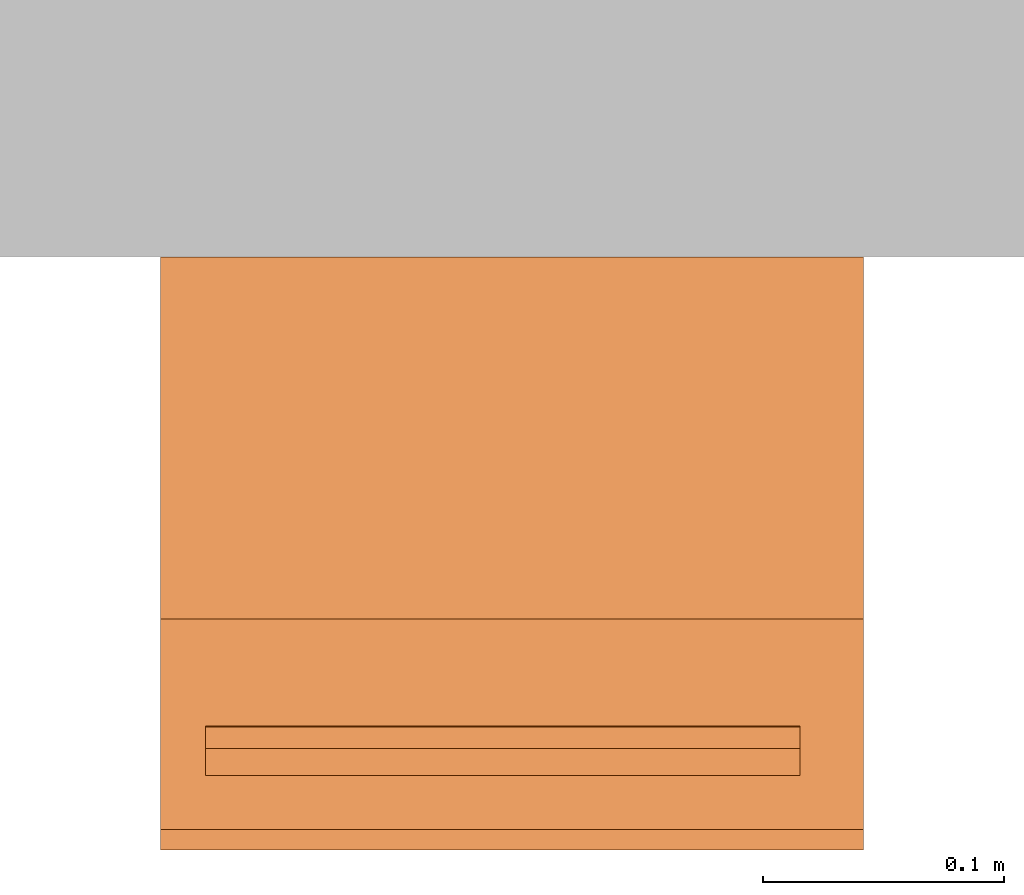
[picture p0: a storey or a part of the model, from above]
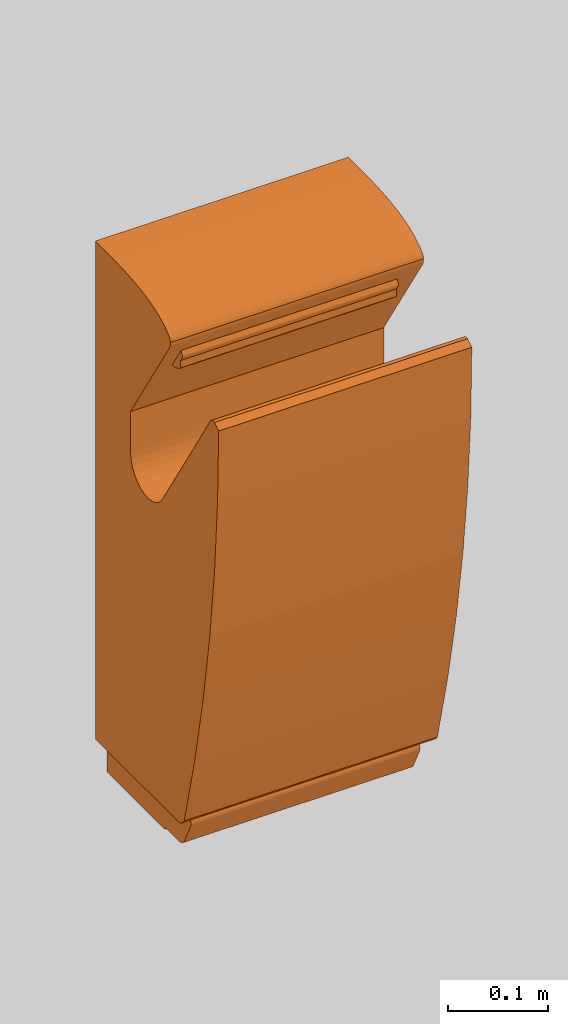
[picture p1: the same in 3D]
Properties of the parts of a building model (IFC2X3)

# File
Description: ViewDefinition [CoordinationView]
File name: Project Number
Time: 2016-07-05T09:52:08
Written by: Autodesk Revit Architecture 2011 - 1.0
Made in: 20100326_1700(x64)

# IfcProject, Project Number
Phase: Project Status

# IfcSite, Default
RefLatitude: 42, 21, 30, 344238; RefLongitude: -71, -3, -35, -194702; RefElevation: 0 mm

# IfcBuilding
Pset_BuildingCommon - NumberOfStoreys: 1
PSet_Revit_Other - Project Issue Date: Issue Date; Project Status: Project Status; Client Name: Owner; Project Address: Enter address here; Project Name: Project Name; Project Number: Project Number

# IfcBuildingStorey, Level 1
Elevation: 0 mm
PSet_Revit_Identity Data - Name: Level 1
PSet_Revit_Constraints - Elevation: 0 mm
PSet_Revit_Type_Graphics - Line Weight: 1; Color: 0; Line Pattern: Centre; Symbol: M_Level Head - Circle; Symbol at End 1 Default: no; Symbol at End 2 Default: yes
PSet_Revit_Type_Constraints - Elevation Base: 0
PSet_Revit_Type_Dimensions - Automatic Room Computation Height: no; Computation Height: 1200 mm

# IfcBuildingElementProxy: Type 1, 510621-2-FR:Type 1:Type 1:229480
In: Level 1
PSet_Revit_Constraints - Level: Level 1; Elevation: 546.922 mm
PSet_Revit_Identity Data - Mark: 55
PSet_Revit_Phasing - Phase Created: New Construction
PSet_Revit_Type_Identity Data - URL: http://www.delabie.fr; Type Comments: Sèche-mains à air pulsé; Technologie: Air pulsé; Référence: 510621; Profondeur: 250 mm; Model: Sèche-mains SPEEDJET; Manufacturer: DELABIE; Lien notice d'installation: http://www.delabie.fr/produits/510621; Lien fiche produit: http://www.delabie.fr/produits/510621; Lien certification: http://www.delabie.fr/produits/510621; Lien CCTP: http://www.delabie.fr/produits/510621; Largeur: 292 mm; Hauteur: 650 mm; Famille de produits: Sèche-mains; Description: DELABIE, fabricant français, est le leader européen de l'équipement sanitaire pour les établissements recevant du public. Robinetteries, solutions pour personnes à mobilité réduite, appareils sanitaires, destinés aux écoles, lieux de loisirs, bureaux, hôpitaux, aéroports, ...; Descriptif: Sèche-mains à air pulsé bi-direction. Mise en marche automatique par détection infrarouge. Technologie intelligente : arrêt automatique au retrait des mains ou après 18 secondes de séchage. Écran LCD avec mode d’emploi animé. Ultra-rapide : séchage en 10 à 18 secondes. Récupérateur d’eau amovible empêchant tout écoulement sur le mur ou le sol : entretien et nettoyage facilité. Filtre à air antibactérien et filtre à charbon actif. Dimensions : 250 x 292 x 650 mm. Poids : 11,4 kg. Type de moteur : brushless sans usure. Économie d’énergie : puissance 850 W. Sans élément chauffant. 220-240 V~ / 50-60 Hz. Débit d’air : 42 l/seconde. Vitesse air : 310 km/h. Niveau sonore : 75-80 dBA. Classe I, IP22. CE. Garantie 3 ans.; OmniClass Number: 23.45.00.00; OmniClass Title: Sanitary, Laundry, and Cleaning Equipment

# IfcWallStandardCase: Basic Wall:Generic - 200mm:398, Basic Wall:Generic - 200mm:127598
In: Level 1
Material: Default Wall 200 mm
Pset_WallCommon - Reference: Basic Wall:Generic - 200mm; LoadBearing: no; ExtendToStructure: no; IsExternal: yes
PSet_Revit_Constraints - Location Line: 0; Base Constraint: Level 1; Base Offset: 0 mm; Base is Attached: no; Base Extension Distance: 0 mm; Unconnected Height: 2500 mm; Top Offset: 0 mm; Top is Attached: no; Top Extension Distance: 0 mm; Room Bounding: yes; Related to Mass: no
PSet_Revit_Phasing - Phase Created: New Construction
PSet_Revit_Structural - Structural Usage: 0
PSet_Revit_Dimensions - Length: 2000 mm; Area: 5000000 mm2; Volume: 1000000000 mm3
PSet_Revit_Type_Construction - Wrapping at Inserts: 0; Wrapping at Ends: 0; Width: 200 mm; Function: 1
PSet_Revit_Type_Graphics - Coarse Scale Fill Color: 0
